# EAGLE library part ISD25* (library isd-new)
Single-chip, multiple messages voice record/playback devices, 60-, 75-, 90-, and 120-second duration.

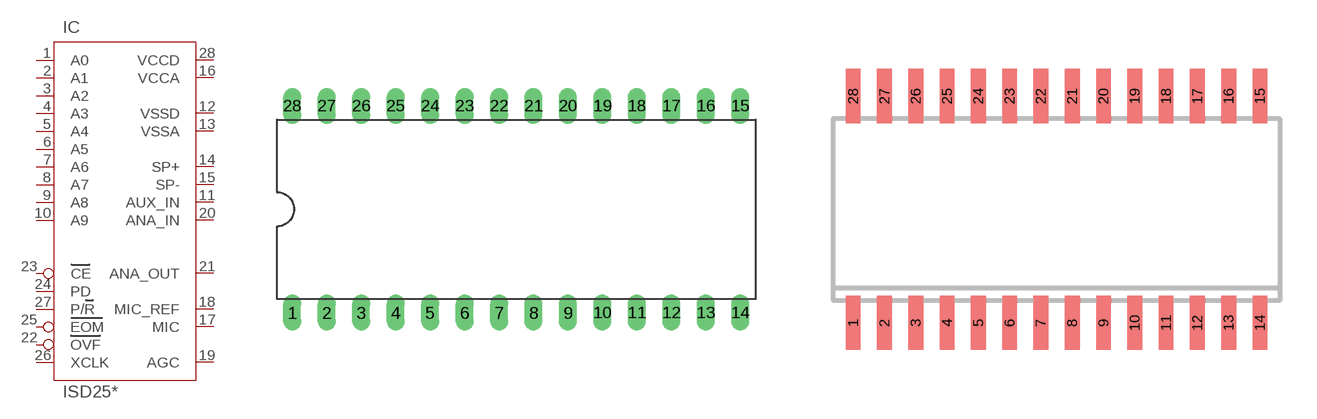
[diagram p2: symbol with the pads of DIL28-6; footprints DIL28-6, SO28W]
Designator prefix IC

## ISD25120P, ISD2560P, ISD2575P, ISD2590P  [DIL28-6]
1  A0  in
2  A1  in
3  A2  in
4  A3  in
5  A4  in
6  A5  in
7  A6  in
8  A7  in
9  A8  in
10  A9  in
11  AUX_IN  in
12  VSSD  pwr
13  VSSA  pwr
14  SP+  out
15  SP-  out
16  VCCA  pwr
17  MIC  in
18  MIC_REF  in
19  AGC  pas
20  ANA_IN  in
21  ANA_OUT  out
22  OVF  out
23  CE  in
24  PD  in
25  EOM  out
26  XCLK  in
27  P/R  in
28  VCCD  pwr

## ISD25120S, ISD2560S, ISD2575S, ISD2590S  [SO28W]
Pads as for DIL28-6

## ISD2560E, ISD2575E, ISD2590E  [TSOP]
1  OVF  out
2  CE  in
3  PD  in
4  EOM  out
5  XCLK  in
6  P/R  in
7  VCCD  pwr
8  A0  in
9  A1  in
10  A2  in
11  A3  in
12  A4  in
13  A5  in
14  A6  in
15  A7  in
16  A8  in
17  A9  in
18  AUX_IN  in
19  VSSD  pwr
20  VSSA  pwr
21  SP+  out
22  SP-  out
23  VCCA  pwr
24  MIC  in
25  MIC_REF  in
26  AGC  pas
27  ANA_IN  in
28  ANA_OUT  out

## Footprint DIL28-6 (pad centres in mm)
Dual In Line Package 0.6 inch (15.24 mm)
drill 0.813 long: 1 -16.51,-7.62; 2 -13.97,-7.62; 3 -11.43,-7.62; 4 -8.89,-7.62; 5 -6.35,-7.62; 6 -3.81,-7.62; 7 -1.27,-7.62; 8 1.27,-7.62; 9 3.81,-7.62; 10 6.35,-7.62; 11 8.89,-7.62; 12 11.43,-7.62; 13 13.97,-7.62; 14 16.51,-7.62; 15 16.51,7.62; 16 13.97,7.62; 17 11.43,7.62; 18 8.89,7.62; 19 6.35,7.62; 20 3.81,7.62; 21 1.27,7.62; 22 -1.27,7.62; 23 -3.81,7.62; 24 -6.35,7.62; 25 -8.89,7.62; 26 -11.43,7.62; 27 -13.97,7.62; 28 -16.51,7.62

## Footprint SO28W (pad centres in mm)
Wide Small Outline Package
smd 0.6 x 2.2: 1 -8.255,-4.6; 2 -6.985,-4.6; 3 -5.715,-4.6; 4 -4.445,-4.6; 5 -3.175,-4.6; 6 -1.905,-4.6; 7 -0.635,-4.6; 8 0.635,-4.6; 9 1.905,-4.6; 10 3.175,-4.6; 11 4.445,-4.6; 12 5.715,-4.6; 13 6.985,-4.6; 14 8.255,-4.6; 15 8.255,4.6; 16 6.985,4.6; 17 5.715,4.6; 18 4.445,4.6; 19 3.175,4.6; 20 1.905,4.6; 21 0.635,4.6; 22 -0.635,4.6; 23 -1.905,4.6; 24 -3.175,4.6; 25 -4.445,4.6; 26 -5.715,4.6; 27 -6.985,4.6; 28 -8.255,4.6

## Footprint TSOP (pad centres in mm)
Plastic Thin Small Outline Package (TSOP) Type 1
smd 0.6 x 0.3: 1 -6.45,3.85; 2 -6.45,3.3; 3 -6.45,2.75; 4 -6.45,2.2; 5 -6.45,1.65; 6 -6.45,1.1; 7 -6.45,0.55; 8 -6.45,0; 9 -6.45,-0.55; 10 -6.45,-1.1; 11 -6.45,-1.65; 12 -6.45,-2.2; 13 -6.45,-2.75; 14 -6.45,-3.3; 15 6.45,-3.3; 16 6.45,-2.75; 17 6.45,-2.2; 18 6.45,-1.65; 19 6.45,-1.1; 20 6.45,-0.55; 21 6.45,0; 22 6.45,0.55; 23 6.45,1.1; 24 6.45,1.65; 25 6.45,2.2; 26 6.45,2.75; 27 6.45,3.3; 28 6.45,3.85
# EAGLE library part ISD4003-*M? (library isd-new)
Single-chip, multiple messages voice record/playback devices, 4-, 5-, 6-, and 8-minute duration.

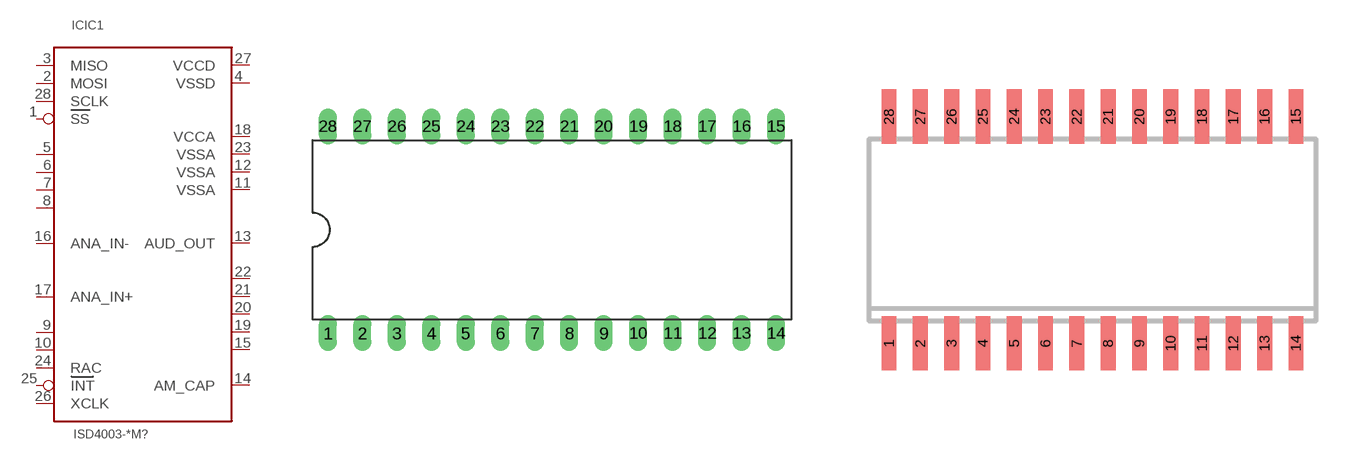
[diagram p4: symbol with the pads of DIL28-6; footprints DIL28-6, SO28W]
Designator prefix IC; gates IC1=ISD4000 G$1=NC-LEFT G$2=NC-LEFT G$3=NC-LEFT G$4=NC-LEFT G$5=NC-LEFT G$6=NC-LEFT G$7=NC-RIGHT G$8=NC-RIGHT G$9=NC-RIGHT G$10=NC-RIGHT G$11=NC-RIGHT

## ISD4003-04MP, ISD4003-05MP, ISD4003-06MP, ISD4003-08MP  [DIL28-6]
1  IC1:SS  in
2  IC1:MOSI  in
3  IC1:MISO  out
4  IC1:VSSD  pwr
5  G$1:NC  nc
6  G$2:NC  nc
7  G$3:NC  nc
8  G$4:NC  nc
9  G$5:NC  nc
10  G$6:NC  nc
11  IC1:VSSA  pwr
12  IC1:VSSA  pwr
13  IC1:AUD_OUT  in
14  IC1:AM_CAP  in
15  G$7:NC  nc
16  IC1:ANA_IN-  in
17  IC1:ANA_IN+  in
18  IC1:VCCA  pwr
19  G$8:NC  nc
20  G$9:NC  nc
21  G$10:NC  nc
22  G$11:NC  nc
23  IC1:VSSA  pwr
24  IC1:RAC  out
25  IC1:INT  out
26  IC1:XCLK  in
27  IC1:VCCD  pwr
28  IC1:SCLK  in

## ISD4003-04MS, ISD4003-05MS, ISD4003-06MS, ISD4003-08MS  [SO28W]
Pads as for DIL28-6

## ISD4003-04MSI, ISD4003-05MSI, ISD4003-06MSI, ISD4003-08MSI  [SO28W]
Pads as for DIL28-6

## ISD4003-04ME, ISD4003-05ME, ISD4003-06ME, ISD4003-08ME  [TSOP]
1  IC1:VSSA  pwr
2  IC1:RAC  out
3  G$1:NC  nc
4  G$2:NC  nc
5  IC1:INT  out
6  IC1:XCLK  in
7  IC1:VCCD  pwr
8  IC1:SCLK  in
9  IC1:SS  in
10  IC1:MOSI  in
11  IC1:MISO  out
12  IC1:VSSD  pwr
13  G$3:NC  nc
14  G$4:NC  nc
15  G$5:NC  nc
16  G$6:NC  nc
17  IC1:VSSA  pwr
18  IC1:VSSA  pwr
19  G$7:NC  nc
20  IC1:AUD_OUT  in
21  G$8:NC  nc
22  IC1:AM_CAP  in
23  G$9:NC  nc
24  IC1:ANA_IN-  in
25  IC1:ANA_IN+  in
26  IC1:VCCA  pwr
27  G$10:NC  nc
28  G$11:NC  nc

## ISD4003-04MED, ISD4003-05MED, ISD4003-06MED, ISD4003-08MED  [TSOP]
Pads as for TSOP

## ISD4003-04MEI, ISD4003-05MEI, ISD4003-06MEI, ISD4003-08MEI  [TSOP]
Pads as for TSOP

## Footprint DIL28-6 (pad centres in mm)
Dual In Line Package 0.6 inch (15.24 mm)
drill 0.813 long: 1 -16.51,-7.62; 2 -13.97,-7.62; 3 -11.43,-7.62; 4 -8.89,-7.62; 5 -6.35,-7.62; 6 -3.81,-7.62; 7 -1.27,-7.62; 8 1.27,-7.62; 9 3.81,-7.62; 10 6.35,-7.62; 11 8.89,-7.62; 12 11.43,-7.62; 13 13.97,-7.62; 14 16.51,-7.62; 15 16.51,7.62; 16 13.97,7.62; 17 11.43,7.62; 18 8.89,7.62; 19 6.35,7.62; 20 3.81,7.62; 21 1.27,7.62; 22 -1.27,7.62; 23 -3.81,7.62; 24 -6.35,7.62; 25 -8.89,7.62; 26 -11.43,7.62; 27 -13.97,7.62; 28 -16.51,7.62

## Footprint SO28W (pad centres in mm)
Wide Small Outline Package
smd 0.6 x 2.2: 1 -8.255,-4.6; 2 -6.985,-4.6; 3 -5.715,-4.6; 4 -4.445,-4.6; 5 -3.175,-4.6; 6 -1.905,-4.6; 7 -0.635,-4.6; 8 0.635,-4.6; 9 1.905,-4.6; 10 3.175,-4.6; 11 4.445,-4.6; 12 5.715,-4.6; 13 6.985,-4.6; 14 8.255,-4.6; 15 8.255,4.6; 16 6.985,4.6; 17 5.715,4.6; 18 4.445,4.6; 19 3.175,4.6; 20 1.905,4.6; 21 0.635,4.6; 22 -0.635,4.6; 23 -1.905,4.6; 24 -3.175,4.6; 25 -4.445,4.6; 26 -5.715,4.6; 27 -6.985,4.6; 28 -8.255,4.6

## Footprint TSOP (pad centres in mm)
Plastic Thin Small Outline Package (TSOP) Type 1
smd 0.6 x 0.3: 1 -6.45,3.85; 2 -6.45,3.3; 3 -6.45,2.75; 4 -6.45,2.2; 5 -6.45,1.65; 6 -6.45,1.1; 7 -6.45,0.55; 8 -6.45,0; 9 -6.45,-0.55; 10 -6.45,-1.1; 11 -6.45,-1.65; 12 -6.45,-2.2; 13 -6.45,-2.75; 14 -6.45,-3.3; 15 6.45,-3.3; 16 6.45,-2.75; 17 6.45,-2.2; 18 6.45,-1.65; 19 6.45,-1.1; 20 6.45,-0.55; 21 6.45,0; 22 6.45,0.55; 23 6.45,1.1; 24 6.45,1.65; 25 6.45,2.2; 26 6.45,2.75; 27 6.45,3.3; 28 6.45,3.85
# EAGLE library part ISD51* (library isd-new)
Single chip, 1 to 16 minutes duration voice record/playback devices with digital storage capability.

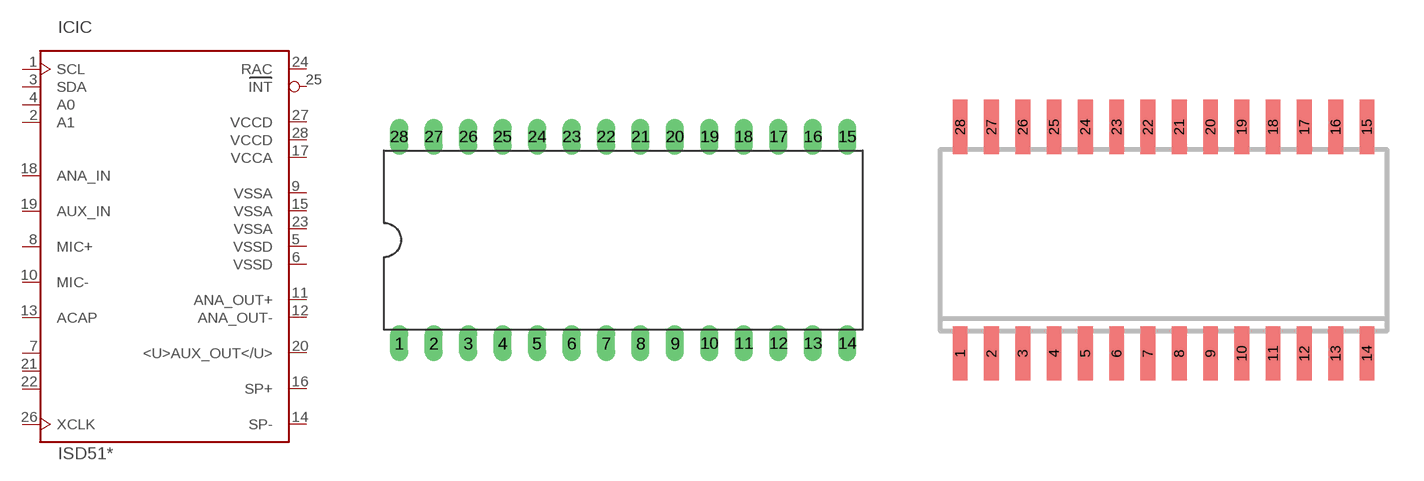
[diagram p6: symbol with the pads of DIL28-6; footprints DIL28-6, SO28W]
Designator prefix IC; gates IC=ISD5100 G$2=NC-LEFT G$3=NC-LEFT G$4=NC-LEFT

## ISD5116P  [DIL28-6]
1  IC:SCL  in
2  IC:A1  in
3  IC:SDA  in
4  IC:A0  in
5  IC:VSSD  out
6  IC:VSSD  out
7  G$2:NC  nc
8  IC:MIC+  in
9  IC:VSSA  out
10  IC:MIC-  in
11  IC:ANA_OUT+  out
12  IC:ANA_OUT-  out
13  IC:ACAP  in
14  IC:SP-  out
15  IC:VSSA  out
16  IC:SP+  out
17  IC:VCCA  out
18  IC:ANA_IN  in
19  IC:AUX_IN  in
20  IC:<U>AUX_OUT</U>  out
21  G$3:NC  nc
22  G$4:NC  nc
23  IC:VSSA  out
24  IC:RAC  out
25  IC:INT  out
26  IC:XCLK  in
27  IC:VCCD  out
28  IC:VCCD  out

## ISD5102S  [SO28W]
Pads as for DIL28-6

## ISD5104S  [SO28W]
Pads as for DIL28-6

## ISD5108S  [SO28W]
Pads as for DIL28-6

## ISD5116S  [SO28W]
Pads as for DIL28-6

## ISD5102E  [TSOP]
1  G$2:NC  nc
2  IC:VSSA  out
3  IC:RAC  out
4  IC:INT  out
5  IC:XCLK  in
6  IC:VCCD  out
7  IC:VCCD  out
8  IC:SCL  in
9  IC:A1  in
10  IC:SDA  in
11  IC:A0  in
12  IC:VSSD  out
13  IC:VSSD  out
14  G$3:NC  nc
15  IC:VSSA  out
16  IC:MIC+  in
17  IC:MIC-  in
18  IC:ANA_OUT+  out
19  IC:ANA_OUT-  out
20  IC:ACAP  in
21  IC:SP-  out
22  IC:VSSA  out
23  IC:SP+  out
24  IC:VCCA  out
25  IC:ANA_IN  in
26  IC:AUX_IN  in
27  IC:<U>AUX_OUT</U>  out
28  G$4:NC  nc

## ISD5104E  [TSOP]
Pads as for TSOP

## ISD5108E  [TSOP]
Pads as for TSOP

## ISD5116E  [TSOP]
Pads as for TSOP

## Footprint DIL28-6 (pad centres in mm)
Dual In Line Package 0.6 inch (15.24 mm)
drill 0.813 long: 1 -16.51,-7.62; 2 -13.97,-7.62; 3 -11.43,-7.62; 4 -8.89,-7.62; 5 -6.35,-7.62; 6 -3.81,-7.62; 7 -1.27,-7.62; 8 1.27,-7.62; 9 3.81,-7.62; 10 6.35,-7.62; 11 8.89,-7.62; 12 11.43,-7.62; 13 13.97,-7.62; 14 16.51,-7.62; 15 16.51,7.62; 16 13.97,7.62; 17 11.43,7.62; 18 8.89,7.62; 19 6.35,7.62; 20 3.81,7.62; 21 1.27,7.62; 22 -1.27,7.62; 23 -3.81,7.62; 24 -6.35,7.62; 25 -8.89,7.62; 26 -11.43,7.62; 27 -13.97,7.62; 28 -16.51,7.62

## Footprint SO28W (pad centres in mm)
Wide Small Outline Package
smd 0.6 x 2.2: 1 -8.255,-4.6; 2 -6.985,-4.6; 3 -5.715,-4.6; 4 -4.445,-4.6; 5 -3.175,-4.6; 6 -1.905,-4.6; 7 -0.635,-4.6; 8 0.635,-4.6; 9 1.905,-4.6; 10 3.175,-4.6; 11 4.445,-4.6; 12 5.715,-4.6; 13 6.985,-4.6; 14 8.255,-4.6; 15 8.255,4.6; 16 6.985,4.6; 17 5.715,4.6; 18 4.445,4.6; 19 3.175,4.6; 20 1.905,4.6; 21 0.635,4.6; 22 -0.635,4.6; 23 -1.905,4.6; 24 -3.175,4.6; 25 -4.445,4.6; 26 -5.715,4.6; 27 -6.985,4.6; 28 -8.255,4.6

## Footprint TSOP (pad centres in mm)
Plastic Thin Small Outline Package (TSOP) Type 1
smd 0.6 x 0.3: 1 -6.45,3.85; 2 -6.45,3.3; 3 -6.45,2.75; 4 -6.45,2.2; 5 -6.45,1.65; 6 -6.45,1.1; 7 -6.45,0.55; 8 -6.45,0; 9 -6.45,-0.55; 10 -6.45,-1.1; 11 -6.45,-1.65; 12 -6.45,-2.2; 13 -6.45,-2.75; 14 -6.45,-3.3; 15 6.45,-3.3; 16 6.45,-2.75; 17 6.45,-2.2; 18 6.45,-1.65; 19 6.45,-1.1; 20 6.45,-0.55; 21 6.45,0; 22 6.45,0.55; 23 6.45,1.1; 24 6.45,1.65; 25 6.45,2.2; 26 6.45,2.75; 27 6.45,3.3; 28 6.45,3.85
